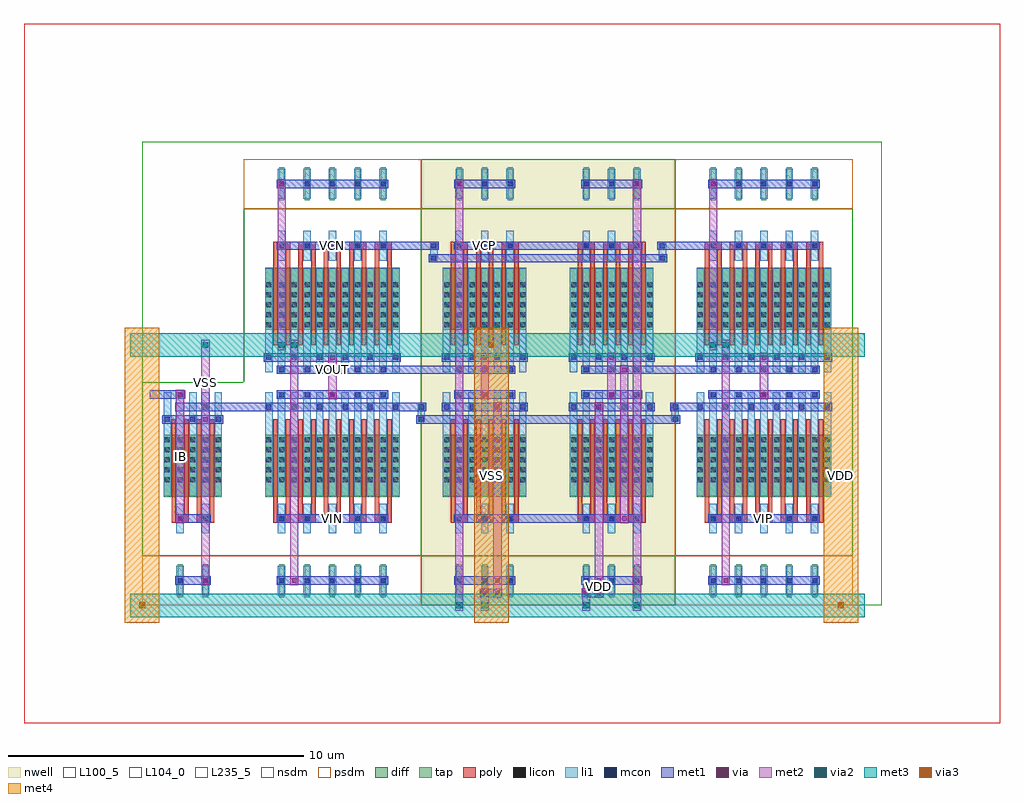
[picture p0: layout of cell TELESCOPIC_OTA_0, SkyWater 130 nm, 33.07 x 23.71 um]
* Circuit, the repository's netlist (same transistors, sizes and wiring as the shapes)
* NGSPICE file created from TELESCOPIC_OTA_0.ext - technology: sky130A

.subckt PMOS_4T_54671542_X3_Y1_1772448769 a_230_357# a_200_252# a_147_357# w_0_0#
X0 a_230_357# a_200_252# a_147_357# w_0_0# sky130_fd_pr__pfet_01v8 ad=0.294 pd=2.38 as=0.5565 ps=4.73 w=2.1 l=0.15 M=6
.ends

.subckt SCM_NMOS_4295876_X1_Y1_1772448771 a_200_252# a_402_357# a_147_357#
X0 a_200_252# a_200_252# a_147_357# a_147_357# sky130_fd_pr__nfet_01v8 ad=0.294 pd=2.38 as=0.5565 ps=4.73 w=2.1 l=0.15 M=2
X1 a_402_357# a_200_252# a_147_357# a_147_357# sky130_fd_pr__nfet_01v8 ad=0.294 pd=2.38 as=0.294 ps=2.38 w=2.1 l=0.15 M=2
.ends

.subckt NMOS_4T_2477428_X5_Y1_1772448768 a_230_357# a_200_252# a_147_357# a_241_1232#
X0 a_230_357# a_200_252# a_147_357# a_241_1232# sky130_fd_pr__nfet_01v8 ad=0.294 pd=2.38 as=0.294 ps=2.38 w=2.1 l=0.15 M=10
.ends

.subckt PMOS_S_62155954_X3_Y1_1772448770 a_230_357# a_200_252# w_0_0#
X0 a_230_357# a_200_252# w_0_0# w_0_0# sky130_fd_pr__pfet_01v8 ad=0.294 pd=2.38 as=0.5565 ps=4.73 w=2.1 l=0.15 M=6
.ends

.subckt TELESCOPIC_OTA_0 IB VCN VOUT VIP VIN VCP VSS VDD
XPMOS_4T_54671542_X3_Y1_1772448769_0 VOUT VCP m1_2290_1400# VDD PMOS_4T_54671542_X3_Y1_1772448769
XPMOS_4T_54671542_X3_Y1_1772448769_1 m1_3236_560# VCP m1_3150_1400# VDD PMOS_4T_54671542_X3_Y1_1772448769
XSCM_NMOS_4295876_X1_Y1_1772448771_0 IB m1_430_1316# VSS SCM_NMOS_4295876_X1_Y1_1772448771
XNMOS_4T_2477428_X5_Y1_1772448768_1 m1_4182_1400# VIP m1_430_1316# VSS NMOS_4T_2477428_X5_Y1_1772448768
XNMOS_4T_2477428_X5_Y1_1772448768_0 m1_1258_1400# VIN m1_430_1316# VSS NMOS_4T_2477428_X5_Y1_1772448768
XNMOS_4T_2477428_X5_Y1_1772448768_2 VOUT VCN m1_1258_1400# VSS NMOS_4T_2477428_X5_Y1_1772448768
XNMOS_4T_2477428_X5_Y1_1772448768_3 m1_3236_560# VCN m1_4182_1400# VSS NMOS_4T_2477428_X5_Y1_1772448768
XPMOS_S_62155954_X3_Y1_1772448770_0 m1_2290_1400# m1_3236_560# VDD PMOS_S_62155954_X3_Y1_1772448770
XPMOS_S_62155954_X3_Y1_1772448770_1 m1_3150_1400# m1_3236_560# VDD PMOS_S_62155954_X3_Y1_1772448770
.ends

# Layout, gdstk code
from math import pi, radians
import gdstk
lib = gdstk.Library(unit=1e-6, precision=1e-09)
def R(c, l, rs):  # rectangles x0, y0, x1, y1
    for r in rs: c.add(gdstk.rectangle(r[:2], r[2:], *l))
def A(c, l, x, y, w, h, nx, ny, dx, dy):  # array of equal rectangles
    R(c, l, [(x+i*dx, y+j*dy, x+i*dx+w, y+j*dy+h) for i in range(nx) for j in range(ny)])
def P(c, l, *ps):  # polygons
    for p in ps: c.add(gdstk.Polygon(p, *l))
nwell = (64, 20)
diff = (65, 20)
tap = (65, 44)
poly = (66, 20)
licon = (66, 44)
li1 = (67, 20)
mcon = (67, 44)
met1 = (68, 20)
via = (68, 44)
met2 = (69, 20)
via2 = (69, 44)
met3 = (70, 20)
via3 = (70, 44)
met4 = (71, 20)
nsdm = (93, 44)
psdm = (94, 20)
L100_5 = (100, 5)
L104_0 = (104, 0)
L235_5 = (235, 5)

scm_nmos_4295876_x1_y1_1 = lib.new_cell('SCM_NMOS_4295876_X1_Y1_1772448771')
R(scm_nmos_4295876_x1_y1_1, diff, [(0.735,1.785,2.705,3.885)])
R(scm_nmos_4295876_x1_y1_1, tap, [(1.205,6.16,1.375,7.28), (2.065,6.16,2.235,7.28)])
A(scm_nmos_4295876_x1_y1_1, poly, 1, 1.26, 0.15, 3.36, 4, 1, 0.43, 0)
R(scm_nmos_4295876_x1_y1_1, poly, [(1,4.485,1.58,4.755), (1.86,4.485,2.44,4.755)])
A(scm_nmos_4295876_x1_y1_1, licon, 0.775, 1.865, 0.17, 0.17, 3, 5, 0.43, 0.34)
A(scm_nmos_4295876_x1_y1_1, licon, 1.635, 1.865, 0.17, 0.17, 3, 5, 0.43, 0.34)
R(scm_nmos_4295876_x1_y1_1, licon, [(1.205,4.535,1.375,4.705), (2.065,4.535,2.235,4.705), (1.205,6.635,1.375,6.805), (2.065,6.635,2.235,6.805)])
A(scm_nmos_4295876_x1_y1_1, li1, 0.735, 0.335, 0.25, 3.53, 5, 1, 0.43, 0)
R(scm_nmos_4295876_x1_y1_1, li1, [(1.165,4.115,1.415,5.125), (2.025,4.115,2.275,5.125), (1.165,6.215,1.415,7.225), (2.025,6.215,2.275,7.225)])
A(scm_nmos_4295876_x1_y1_1, mcon, 0.775, 1.175, 0.17, 0.17, 3, 1, 0.86, 0)
R(scm_nmos_4295876_x1_y1_1, mcon, [(1.205,0.335,1.375,0.505), (2.065,0.755,2.235,0.925), (1.205,4.535,1.375,4.705), (2.065,4.535,2.235,4.705), (1.205,6.635,1.375,6.805), (2.065,6.635,2.235,6.805)])
R(scm_nmos_4295876_x1_y1_1, met1, [(0.26,0.28,1.46,0.56), (1.12,0.7,2.32,0.98), (0.69,1.12,2.75,1.4), (1.12,4.48,2.32,4.76), (1.12,6.58,2.32,6.86)])
R(scm_nmos_4295876_x1_y1_1, via, [(1.215,0.345,1.365,0.495), (2.075,1.185,2.225,1.335), (1.215,4.545,1.365,4.695), (2.075,6.645,2.225,6.795)])
R(scm_nmos_4295876_x1_y1_1, met2, [(1.15,0.26,1.43,4.78), (2.01,1.1,2.29,6.88)])
R(scm_nmos_4295876_x1_y1_1, nsdm, [(0,0,3.44,5.88)])
R(scm_nmos_4295876_x1_y1_1, psdm, [(0,5.88,3.44,7.56)])
R(scm_nmos_4295876_x1_y1_1, L100_5, [(0,0,3.44,7.56)])

pmos_s_62155954_x3_y1_17 = lib.new_cell('PMOS_S_62155954_X3_Y1_1772448770')
R(pmos_s_62155954_x3_y1_17, nwell, [(0,0,4.3,7.56)])
R(pmos_s_62155954_x3_y1_17, diff, [(0.735,1.785,3.565,3.885)])
A(pmos_s_62155954_x3_y1_17, tap, 1.205, 6.16, 0.17, 1.12, 3, 1, 0.86, 0)
A(pmos_s_62155954_x3_y1_17, poly, 1, 1.26, 0.15, 3.36, 6, 1, 0.43, 0)
A(pmos_s_62155954_x3_y1_17, poly, 1, 4.485, 0.58, 0.27, 3, 1, 0.86, 0)
A(pmos_s_62155954_x3_y1_17, licon, 0.775, 1.865, 0.17, 0.17, 3, 5, 0.43, 0.34)
A(pmos_s_62155954_x3_y1_17, licon, 1.635, 1.865, 0.17, 0.17, 3, 5, 0.43, 0.34)
A(pmos_s_62155954_x3_y1_17, licon, 2.495, 1.865, 0.17, 0.17, 3, 5, 0.43, 0.34)
A(pmos_s_62155954_x3_y1_17, licon, 1.205, 4.535, 0.17, 0.17, 3, 2, 0.86, 2.1)
A(pmos_s_62155954_x3_y1_17, li1, 0.735, 0.335, 0.25, 3.53, 7, 1, 0.43, 0)
A(pmos_s_62155954_x3_y1_17, li1, 1.165, 4.115, 0.25, 1.01, 3, 2, 0.86, 2.1)
A(pmos_s_62155954_x3_y1_17, mcon, 1.205, 0.335, 0.17, 0.17, 3, 2, 0.86, 4.2)
A(pmos_s_62155954_x3_y1_17, mcon, 0.775, 0.755, 0.17, 0.17, 4, 1, 0.86, 0)
A(pmos_s_62155954_x3_y1_17, mcon, 1.205, 6.635, 0.17, 0.17, 3, 1, 0.86, 0)
R(pmos_s_62155954_x3_y1_17, met1, [(1.12,0.28,3.18,0.56), (0.69,0.7,3.61,0.98), (1.12,4.48,3.18,4.76), (1.12,6.58,3.18,6.86)])
R(pmos_s_62155954_x3_y1_17, via, [(2.505,0.765,2.655,0.915), (2.505,6.645,2.655,6.795)])
R(pmos_s_62155954_x3_y1_17, met2, [(2.44,0.68,2.72,6.88)])
R(pmos_s_62155954_x3_y1_17, nsdm, [(0,5.88,4.3,7.56)])
R(pmos_s_62155954_x3_y1_17, psdm, [(0,0,4.3,5.88)])
R(pmos_s_62155954_x3_y1_17, L100_5, [(0,0,4.3,7.56)])

nmos_4t_2477428_x5_y1_17 = lib.new_cell('NMOS_4T_2477428_X5_Y1_1772448768')
R(nmos_4t_2477428_x5_y1_17, diff, [(0.735,1.785,5.285,3.885)])
A(nmos_4t_2477428_x5_y1_17, tap, 1.205, 6.16, 0.17, 1.12, 5, 1, 0.86, 0)
A(nmos_4t_2477428_x5_y1_17, poly, 1, 1.26, 0.15, 3.36, 10, 1, 0.43, 0)
A(nmos_4t_2477428_x5_y1_17, poly, 1, 4.485, 0.58, 0.27, 5, 1, 0.86, 0)
A(nmos_4t_2477428_x5_y1_17, licon, 0.775, 1.865, 0.17, 0.17, 3, 5, 0.43, 0.34)
A(nmos_4t_2477428_x5_y1_17, licon, 1.635, 1.865, 0.17, 0.17, 3, 5, 0.43, 0.34)
A(nmos_4t_2477428_x5_y1_17, licon, 2.495, 1.865, 0.17, 0.17, 3, 5, 0.43, 0.34)
A(nmos_4t_2477428_x5_y1_17, licon, 3.355, 1.865, 0.17, 0.17, 3, 5, 0.43, 0.34)
A(nmos_4t_2477428_x5_y1_17, licon, 4.215, 1.865, 0.17, 0.17, 3, 5, 0.43, 0.34)
A(nmos_4t_2477428_x5_y1_17, licon, 1.205, 4.535, 0.17, 0.17, 5, 2, 0.86, 2.1)
A(nmos_4t_2477428_x5_y1_17, li1, 0.735, 0.335, 0.25, 3.53, 11, 1, 0.43, 0)
A(nmos_4t_2477428_x5_y1_17, li1, 1.165, 4.115, 0.25, 1.01, 5, 2, 0.86, 2.1)
A(nmos_4t_2477428_x5_y1_17, mcon, 1.205, 0.335, 0.17, 0.17, 5, 2, 0.86, 4.2)
A(nmos_4t_2477428_x5_y1_17, mcon, 0.775, 0.755, 0.17, 0.17, 6, 1, 0.86, 0)
A(nmos_4t_2477428_x5_y1_17, mcon, 1.205, 6.635, 0.17, 0.17, 5, 1, 0.86, 0)
R(nmos_4t_2477428_x5_y1_17, met1, [(1.12,0.28,4.9,0.56), (0.69,0.7,5.33,0.98), (1.12,4.48,4.9,4.76), (1.12,6.58,4.9,6.86)])
R(nmos_4t_2477428_x5_y1_17, nsdm, [(0,0,6.02,5.88)])
R(nmos_4t_2477428_x5_y1_17, psdm, [(0,5.88,6.02,7.56)])
R(nmos_4t_2477428_x5_y1_17, L100_5, [(0,0,6.02,7.56)])

pmos_4t_54671542_x3_y1_1 = lib.new_cell('PMOS_4T_54671542_X3_Y1_1772448769')
R(pmos_4t_54671542_x3_y1_1, nwell, [(0,0,4.3,7.56)])
R(pmos_4t_54671542_x3_y1_1, diff, [(0.735,1.785,3.565,3.885)])
A(pmos_4t_54671542_x3_y1_1, tap, 1.205, 6.16, 0.17, 1.12, 3, 1, 0.86, 0)
A(pmos_4t_54671542_x3_y1_1, poly, 1, 1.26, 0.15, 3.36, 6, 1, 0.43, 0)
A(pmos_4t_54671542_x3_y1_1, poly, 1, 4.485, 0.58, 0.27, 3, 1, 0.86, 0)
A(pmos_4t_54671542_x3_y1_1, licon, 0.775, 1.865, 0.17, 0.17, 3, 5, 0.43, 0.34)
A(pmos_4t_54671542_x3_y1_1, licon, 1.635, 1.865, 0.17, 0.17, 3, 5, 0.43, 0.34)
A(pmos_4t_54671542_x3_y1_1, licon, 2.495, 1.865, 0.17, 0.17, 3, 5, 0.43, 0.34)
A(pmos_4t_54671542_x3_y1_1, licon, 1.205, 4.535, 0.17, 0.17, 3, 2, 0.86, 2.1)
A(pmos_4t_54671542_x3_y1_1, li1, 0.735, 0.335, 0.25, 3.53, 7, 1, 0.43, 0)
A(pmos_4t_54671542_x3_y1_1, li1, 1.165, 4.115, 0.25, 1.01, 3, 2, 0.86, 2.1)
A(pmos_4t_54671542_x3_y1_1, mcon, 1.205, 0.335, 0.17, 0.17, 3, 2, 0.86, 4.2)
A(pmos_4t_54671542_x3_y1_1, mcon, 0.775, 0.755, 0.17, 0.17, 4, 1, 0.86, 0)
A(pmos_4t_54671542_x3_y1_1, mcon, 1.205, 6.635, 0.17, 0.17, 3, 1, 0.86, 0)
R(pmos_4t_54671542_x3_y1_1, met1, [(1.12,0.28,3.18,0.56), (0.69,0.7,3.61,0.98), (1.12,4.48,3.18,4.76), (1.12,6.58,3.18,6.86)])
R(pmos_4t_54671542_x3_y1_1, nsdm, [(0,5.88,4.3,7.56)])
R(pmos_4t_54671542_x3_y1_1, psdm, [(0,0,4.3,5.88)])
R(pmos_4t_54671542_x3_y1_1, L100_5, [(0,0,4.3,7.56)])

telescopic_ota_0 = lib.new_cell('TELESCOPIC_OTA_0')
R(telescopic_ota_0, li1, [(9.335,6.215,9.585,6.385), (9.335,6.215,9.585,6.385), (17.935,6.215,18.185,6.385), (17.935,6.215,18.185,6.385), (9.335,6.3,9.585,6.72), (17.935,6.3,18.185,6.72), (9.335,6.635,9.585,6.805), (9.335,6.635,9.585,6.805), (17.935,6.635,18.185,6.805), (17.935,6.635,18.185,6.805), (9.765,11.675,10.015,11.845), (9.765,11.675,10.015,11.845), (17.505,11.675,17.755,11.845), (17.505,11.675,17.755,11.845), (9.765,11.76,10.015,12.18), (17.505,11.76,17.755,12.18), (9.765,12.095,10.015,12.265), (9.765,12.095,10.015,12.265), (17.505,12.095,17.755,12.265), (17.505,12.095,17.755,12.265)])
R(telescopic_ota_0, mcon, [(9.375,6.215,9.545,6.385), (9.375,6.215,9.545,6.385), (17.975,6.215,18.145,6.385), (17.975,6.215,18.145,6.385), (9.375,6.635,9.545,6.805), (9.375,6.635,9.545,6.805), (17.975,6.635,18.145,6.805), (17.975,6.635,18.145,6.805), (9.805,11.675,9.975,11.845), (9.805,11.675,9.975,11.845), (17.545,11.675,17.715,11.845), (17.545,11.675,17.715,11.845), (9.805,12.095,9.975,12.265), (9.805,12.095,9.975,12.265), (17.545,12.095,17.715,12.265), (17.545,12.095,17.715,12.265)])
R(telescopic_ota_0, met1, [(11.45,0.28,11.77,0.56), (11.45,0.28,11.77,0.56), (11.45,0.28,11.77,0.56), (11.45,0.28,11.77,0.56), (11.61,0.28,12.04,0.56), (11.88,0.28,12.2,0.56), (11.88,0.28,12.2,0.56), (11.88,0.28,12.2,0.56), (11.88,0.28,12.2,0.56), (14.89,0.28,15.21,0.56), (14.89,0.28,15.21,0.56), (14.89,0.28,15.21,0.56), (14.89,0.28,15.21,0.56), (14.89,0.28,15.21,0.56), (15.05,0.28,15.48,0.56), (15.32,0.28,15.64,0.56), (15.32,0.28,15.64,0.56), (15.32,0.28,15.64,0.56), (15.32,0.28,15.64,0.56), (15.32,0.28,15.64,0.56), (5,0.7,5.32,0.98), (5,0.7,5.32,0.98), (19.62,0.7,19.94,0.98), (19.62,0.7,19.94,0.98), (19.62,0.7,19.94,0.98), (12.47,2.8,15.05,3.08), (16.18,2.8,16.5,3.08), (16.18,2.8,16.5,3.08), (16.18,2.8,16.5,3.08), (16.18,2.8,16.5,3.08), (9.29,6.16,9.63,6.44), (9.29,6.16,9.63,6.44), (9.46,6.16,18.06,6.44), (17.89,6.16,18.23,6.44), (17.89,6.16,18.23,6.44), (2.15,6.58,4.3,6.86), (8.6,6.58,9.46,6.86), (9.29,6.58,9.63,6.86), (9.29,6.58,9.63,6.86), (17.89,6.58,18.23,6.86), (17.89,6.58,18.23,6.86), (18.06,6.58,18.92,6.86), (6.29,7,6.61,7.28), (6.29,7,6.61,7.28), (11.45,7,11.77,7.28), (11.45,7,11.77,7.28), (15.75,7,16.07,7.28), (15.75,7,16.07,7.28), (20.91,7,21.23,7.28), (20.91,7,21.23,7.28), (8.17,7.84,10.75,8.12), (16.18,7.84,16.5,8.12), (16.18,7.84,16.5,8.12), (16.18,7.84,16.5,8.12), (16.18,7.84,16.5,8.12), (16.77,7.84,19.35,8.12), (6.29,8.26,6.61,8.54), (6.29,8.26,6.61,8.54), (11.45,8.26,11.77,8.54), (11.45,8.26,11.77,8.54), (15.75,8.26,16.07,8.54), (15.75,8.26,16.07,8.54), (20.91,8.26,21.23,8.54), (20.91,8.26,21.23,8.54), (9.72,11.62,10.06,11.9), (9.72,11.62,10.06,11.9), (9.89,11.62,17.63,11.9), (17.46,11.62,17.8,11.9), (17.46,11.62,17.8,11.9), (8.17,12.04,9.89,12.32), (9.72,12.04,10.06,12.32), (9.72,12.04,10.06,12.32), (12.47,12.04,15.05,12.32), (17.46,12.04,17.8,12.32), (17.46,12.04,17.8,12.32), (17.63,12.04,19.35,12.32), (4.57,14.14,4.89,14.42), (4.57,14.14,4.89,14.42), (4.57,14.14,4.89,14.42), (4.57,14.14,4.89,14.42), (10.59,14.14,10.91,14.42), (10.59,14.14,10.91,14.42), (16.61,14.14,16.93,14.42), (16.61,14.14,16.93,14.42), (16.61,14.14,16.93,14.42), (19.19,14.14,19.51,14.42), (19.19,14.14,19.51,14.42), (19.19,14.14,19.51,14.42), (19.19,14.14,19.51,14.42), (19.19,14.14,19.51,14.42)])
P(telescopic_ota_0, met1, [(0,0),(0,0),(0,0),(0,0)],
  [(0,0),(0,0),(0,0),(0,0)],
  [(0,0),(0,0),(0,0),(0,0)],
  [(0,0),(0,0),(0,0),(0,0)],
  [(0,0),(0,0),(0,0),(0,0)],
  [(0,0),(0,0),(0,0),(0,0)],
  [(0,0),(0,0),(0,0),(0,0)],
  [(0,0),(0,0),(0,0),(0,0)],
  [(0,0),(0,0),(0,0),(0,0)],
  [(0,0),(0,0),(0,0),(0,0)],
  [(0,0),(0,0),(0,0),(0,0)],
  [(0,0),(0,0),(0,0),(0,0)],
  [(0,0),(0,0),(0,0),(0,0)],
  [(0,0),(0,0),(0,0),(0,0)],
  [(0,0),(0,0),(0,0),(0,0)],
  [(0,0),(0,0),(0,0),(0,0)],
  [(0,0),(0,0),(0,0),(0,0)],
  [(0,0),(0,0),(0,0),(0,0)],
  [(0,0),(0,0),(0,0),(0,0)],
  [(0,0),(0,0),(0,0),(0,0)],
  [(0,0),(0,0),(0,0),(0,0)],
  [(0,0),(0,0),(0,0),(0,0)],
  [(0,0),(0,0),(0,0),(0,0)],
  [(0,0),(0,0),(0,0),(0,0)],
  [(0,0),(0,0),(0,0),(0,0)],
  [(0,0),(0,0),(0,0),(0,0)],
  [(0,0),(0,0),(0,0),(0,0)],
  [(0,0),(0,0),(0,0),(0,0)],
  [(0,0),(0,0),(0,0),(0,0)],
  [(0,0),(0,0),(0,0),(0,0)],
  [(0,0),(0,0),(0,0),(0,0)],
  [(0,0),(0,0),(0,0),(0,0)],
  [(0,0),(0,0),(0,0),(0,0)],
  [(0,0),(0,0),(0,0),(0,0)])
R(telescopic_ota_0, via, [(11.535,0.345,11.685,0.495), (11.535,0.345,11.685,0.495), (11.535,0.345,11.685,0.495), (11.535,0.345,11.685,0.495), (11.965,0.345,12.115,0.495), (11.965,0.345,12.115,0.495), (11.965,0.345,12.115,0.495), (11.965,0.345,12.115,0.495), (14.975,0.345,15.125,0.495), (14.975,0.345,15.125,0.495), (14.975,0.345,15.125,0.495), (14.975,0.345,15.125,0.495), (14.975,0.345,15.125,0.495), (15.405,0.345,15.555,0.495), (15.405,0.345,15.555,0.495), (15.405,0.345,15.555,0.495), (15.405,0.345,15.555,0.495), (15.405,0.345,15.555,0.495), (5.085,0.765,5.235,0.915), (5.085,0.765,5.235,0.915), (19.705,0.765,19.855,0.915), (19.705,0.765,19.855,0.915), (19.705,0.765,19.855,0.915), (16.265,2.865,16.415,3.015), (16.265,2.865,16.415,3.015), (16.265,2.865,16.415,3.015), (16.265,2.865,16.415,3.015), (6.375,7.065,6.525,7.215), (6.375,7.065,6.525,7.215), (11.535,7.065,11.685,7.215), (11.535,7.065,11.685,7.215), (15.835,7.065,15.985,7.215), (15.835,7.065,15.985,7.215), (20.995,7.065,21.145,7.215), (20.995,7.065,21.145,7.215), (16.265,7.905,16.415,8.055), (16.265,7.905,16.415,8.055), (16.265,7.905,16.415,8.055), (16.265,7.905,16.415,8.055), (6.375,8.325,6.525,8.475), (6.375,8.325,6.525,8.475), (11.535,8.325,11.685,8.475), (11.535,8.325,11.685,8.475), (15.835,8.325,15.985,8.475), (15.835,8.325,15.985,8.475), (20.995,8.325,21.145,8.475), (20.995,8.325,21.145,8.475), (4.655,14.205,4.805,14.355), (4.655,14.205,4.805,14.355), (4.655,14.205,4.805,14.355), (4.655,14.205,4.805,14.355), (10.675,14.205,10.825,14.355), (10.675,14.205,10.825,14.355), (16.695,14.205,16.845,14.355), (16.695,14.205,16.845,14.355), (16.695,14.205,16.845,14.355), (19.275,14.205,19.425,14.355), (19.275,14.205,19.425,14.355), (19.275,14.205,19.425,14.355), (19.275,14.205,19.425,14.355), (19.275,14.205,19.425,14.355)])
R(telescopic_ota_0, met2, [(10.61,-0.185,10.89,0.185), (10.61,-0.185,10.89,0.185), (11.47,-0.185,11.75,0.185), (11.47,-0.185,11.75,0.185), (11.47,-0.185,11.75,0.185), (11.47,-0.185,11.75,0.185), (14.91,-0.185,15.19,0.185), (14.91,-0.185,15.19,0.185), (14.91,-0.185,15.19,0.185), (14.91,-0.185,15.19,0.185), (14.91,-0.185,15.19,0.185), (16.63,-0.185,16.91,0.185), (16.63,-0.185,16.91,0.185), (16.63,-0.185,16.91,0.185), (10.61,0,10.89,14.28), (11.47,0,11.75,0.42), (14.91,0,15.19,0.42), (16.63,0,16.91,14.28), (11.47,0.26,11.75,0.58), (11.47,0.26,11.75,0.58), (11.47,0.26,11.75,0.58), (11.47,0.26,11.75,0.58), (11.9,0.26,12.18,0.58), (11.9,0.26,12.18,0.58), (11.9,0.26,12.18,0.58), (11.9,0.26,12.18,0.58), (14.91,0.26,15.19,0.58), (14.91,0.26,15.19,0.58), (14.91,0.26,15.19,0.58), (14.91,0.26,15.19,0.58), (14.91,0.26,15.19,0.58), (15.34,0.26,15.62,0.58), (15.34,0.26,15.62,0.58), (15.34,0.26,15.62,0.58), (15.34,0.26,15.62,0.58), (15.34,0.26,15.62,0.58), (11.9,0.42,12.18,0.84), (15.34,0.42,15.62,0.84), (5.02,0.68,5.3,1), (5.02,0.68,5.3,1), (19.64,0.68,19.92,1), (19.64,0.68,19.92,1), (19.64,0.68,19.92,1), (5.02,0.84,5.3,8.82), (19.64,0.84,19.92,8.82), (16.2,2.78,16.48,3.1), (16.2,2.78,16.48,3.1), (16.2,2.78,16.48,3.1), (16.2,2.78,16.48,3.1), (16.2,2.94,16.48,7.98), (2.01,6.3,2.29,8.82), (6.31,6.98,6.59,7.3), (6.31,6.98,6.59,7.3), (11.47,6.98,11.75,7.3), (11.47,6.98,11.75,7.3), (15.77,6.98,16.05,7.3), (15.77,6.98,16.05,7.3), (20.93,6.98,21.21,7.3), (20.93,6.98,21.21,7.3), (6.31,7.14,6.59,8.4), (11.47,7.14,11.75,8.4), (15.77,7.14,16.05,8.4), (20.93,7.14,21.21,8.4), (16.2,7.82,16.48,8.14), (16.2,7.82,16.48,8.14), (16.2,7.82,16.48,8.14), (16.2,7.82,16.48,8.14), (6.31,8.24,6.59,8.56), (6.31,8.24,6.59,8.56), (11.47,8.24,11.75,8.56), (11.47,8.24,11.75,8.56), (15.77,8.24,16.05,8.56), (15.77,8.24,16.05,8.56), (20.93,8.24,21.21,8.56), (20.93,8.24,21.21,8.56), (2.01,8.635,2.29,9.005), (2.01,8.635,2.29,9.005), (2.01,8.635,2.29,9.005), (2.01,8.635,2.29,9.005), (2.01,8.635,2.29,9.005), (2.01,8.635,2.29,9.005), (4.59,8.635,4.87,9.005), (4.59,8.635,4.87,9.005), (4.59,8.635,4.87,9.005), (4.59,8.635,4.87,9.005), (5.02,8.635,5.3,9.005), (5.02,8.635,5.3,9.005), (19.21,8.635,19.49,9.005), (19.21,8.635,19.49,9.005), (19.21,8.635,19.49,9.005), (19.21,8.635,19.49,9.005), (19.21,8.635,19.49,9.005), (19.64,8.635,19.92,9.005), (19.64,8.635,19.92,9.005), (19.64,8.635,19.92,9.005), (4.59,8.82,4.87,14.28), (19.21,8.82,19.49,14.28), (4.59,14.12,4.87,14.44), (4.59,14.12,4.87,14.44), (4.59,14.12,4.87,14.44), (4.59,14.12,4.87,14.44), (10.61,14.12,10.89,14.44), (10.61,14.12,10.89,14.44), (16.63,14.12,16.91,14.44), (16.63,14.12,16.91,14.44), (16.63,14.12,16.91,14.44), (19.21,14.12,19.49,14.44), (19.21,14.12,19.49,14.44), (19.21,14.12,19.49,14.44), (19.21,14.12,19.49,14.44), (19.21,14.12,19.49,14.44)])
P(telescopic_ota_0, met2, [(0,0),(0,0),(0,0),(0,0)],
  [(0,0),(0,0),(0,0),(0,0)],
  [(0,0),(0,0),(0,0),(0,0)],
  [(0,0),(0,0),(0,0),(0,0)],
  [(0,0),(0,0),(0,0),(0,0)])
R(telescopic_ota_0, via2, [(10.65,-0.1,10.85,0.1), (10.65,-0.1,10.85,0.1), (11.51,-0.1,11.71,0.1), (11.51,-0.1,11.71,0.1), (11.51,-0.1,11.71,0.1), (11.51,-0.1,11.71,0.1), (14.95,-0.1,15.15,0.1), (14.95,-0.1,15.15,0.1), (14.95,-0.1,15.15,0.1), (14.95,-0.1,15.15,0.1), (14.95,-0.1,15.15,0.1), (16.67,-0.1,16.87,0.1), (16.67,-0.1,16.87,0.1), (16.67,-0.1,16.87,0.1), (2.05,8.72,2.25,8.92), (2.05,8.72,2.25,8.92), (2.05,8.72,2.25,8.92), (2.05,8.72,2.25,8.92), (2.05,8.72,2.25,8.92), (2.05,8.72,2.25,8.92), (4.63,8.72,4.83,8.92), (4.63,8.72,4.83,8.92), (4.63,8.72,4.83,8.92), (4.63,8.72,4.83,8.92), (5.06,8.72,5.26,8.92), (5.06,8.72,5.26,8.92), (19.25,8.72,19.45,8.92), (19.25,8.72,19.45,8.92), (19.25,8.72,19.45,8.92), (19.25,8.72,19.45,8.92), (19.25,8.72,19.45,8.92), (19.68,8.72,19.88,8.92), (19.68,8.72,19.88,8.92), (19.68,8.72,19.88,8.92)])
A(telescopic_ota_0, met3, -0.4, -0.4, 4.24, 0.8, 3, 2, 3.44, 8.82)
R(telescopic_ota_0, met3, [(-0.165,-0.4,0.165,0.4), (9.92,-0.4,12.24,0.4), (10.585,-0.4,10.915,0.4), (10.585,-0.4,10.915,0.4), (11.44,-0.4,14.16,0.4), (11.445,-0.4,11.775,0.4), (11.445,-0.4,11.775,0.4), (11.445,-0.4,11.775,0.4), (11.445,-0.4,11.775,0.4), (13.36,-0.4,17.6,0.4), (14.885,-0.4,15.215,0.4), (14.885,-0.4,15.215,0.4), (14.885,-0.4,15.215,0.4), (14.885,-0.4,15.215,0.4), (14.885,-0.4,15.215,0.4), (16.605,-0.4,16.935,0.4), (16.605,-0.4,16.935,0.4), (16.605,-0.4,16.935,0.4), (16.8,-0.4,21.04,0.4), (20.24,-0.4,24.08,0.4), (23.28,-0.4,24.48,0.4), (23.515,-0.4,23.845,0.4), (1.985,8.42,2.315,9.22), (1.985,8.42,2.315,9.22), (1.985,8.42,2.315,9.22), (1.985,8.42,2.315,9.22), (1.985,8.42,2.315,9.22), (1.985,8.42,2.315,9.22), (4.565,8.42,4.895,9.22), (4.565,8.42,4.895,9.22), (4.565,8.42,4.895,9.22), (4.565,8.42,4.895,9.22), (4.995,8.42,5.325,9.22), (4.995,8.42,5.325,9.22), (9.92,8.42,12.24,9.22), (11.44,8.42,14.16,9.22), (11.675,8.42,12.005,9.22), (13.36,8.42,17.6,9.22), (16.8,8.42,21.04,9.22), (19.185,8.42,19.515,9.22), (19.185,8.42,19.515,9.22), (19.185,8.42,19.515,9.22), (19.185,8.42,19.515,9.22), (19.185,8.42,19.515,9.22), (19.615,8.42,19.945,9.22), (19.615,8.42,19.945,9.22), (19.615,8.42,19.945,9.22), (20.24,8.42,24.08,9.22), (23.28,8.42,24.48,9.22)])
R(telescopic_ota_0, via3, [(-0.1,-0.1,0.1,0.1), (23.58,-0.1,23.78,0.1), (11.74,8.72,11.94,8.92)])
A(telescopic_ota_0, met4, -0.59, -0.59, 1.18, 10, 3, 1, 11.84, 0)
R(telescopic_ota_0, met4, [(-0.59,-0.165,0.59,0.165), (23.09,-0.165,24.27,0.165), (11.25,8.655,12.43,8.985)])
R(telescopic_ota_0, L104_0, [(-4,-4,29.07,19.71)])
R(telescopic_ota_0, L235_5, [(0,0,25.07,15.71)])
telescopic_ota_0.add(gdstk.Reference(scm_nmos_4295876_x1_y1_1, (0,7.56), x_reflection=True))
telescopic_ota_0.add(gdstk.Reference(pmos_s_62155954_x3_y1_17, (18.06,7.56), rotation=pi))
telescopic_ota_0.add(gdstk.Reference(pmos_s_62155954_x3_y1_17, (9.46,7.56), x_reflection=True))
telescopic_ota_0.add(gdstk.Reference(nmos_4t_2477428_x5_y1_17, (24.08,7.56), rotation=pi, x_reflection=True))
telescopic_ota_0.add(gdstk.Reference(nmos_4t_2477428_x5_y1_17, (3.44,7.56)))
telescopic_ota_0.add(gdstk.Reference(nmos_4t_2477428_x5_y1_17, (18.06,7.56), x_reflection=True))
telescopic_ota_0.add(gdstk.Reference(nmos_4t_2477428_x5_y1_17, (9.46,7.56), rotation=pi))
telescopic_ota_0.add(gdstk.Reference(pmos_4t_54671542_x3_y1_1, (13.76,7.56)))
telescopic_ota_0.add(gdstk.Reference(pmos_4t_54671542_x3_y1_1, (13.76,7.56), rotation=pi, x_reflection=True))
telescopic_ota_0.add(gdstk.Label('IB', (1.29,5.04), layer=69, texttype=5))
telescopic_ota_0.add(gdstk.Label('VCN', (6.45,12.18), layer=68, texttype=5))
telescopic_ota_0.add(gdstk.Label('VOUT', (6.45,7.98), layer=68, texttype=5))
telescopic_ota_0.add(gdstk.Label('VIP', (21.07,2.94), layer=68, texttype=5))
telescopic_ota_0.add(gdstk.Label('VIN', (6.45,2.94), layer=68, texttype=5))
telescopic_ota_0.add(gdstk.Label('VCP', (11.61,12.18), layer=68, texttype=5))
telescopic_ota_0.add(gdstk.Label('VSS', (2.15,7.56), layer=69, texttype=5))
telescopic_ota_0.add(gdstk.Label('VSS', (11.84,4.41), layer=71, texttype=5))
telescopic_ota_0.add(gdstk.Label('VSS', (11.84,4.41), layer=71, texttype=5))
telescopic_ota_0.add(gdstk.Label('VSS', (11.84,4.41), layer=71, texttype=5))
telescopic_ota_0.add(gdstk.Label('VSS', (11.84,4.41), layer=71, texttype=5))
telescopic_ota_0.add(gdstk.Label('VSS', (11.84,4.41), layer=71, texttype=5))
telescopic_ota_0.add(gdstk.Label('VSS', (11.84,4.41), layer=71, texttype=5))
telescopic_ota_0.add(gdstk.Label('VSS', (11.84,4.41), layer=71, texttype=5))
telescopic_ota_0.add(gdstk.Label('VSS', (11.84,4.41), layer=71, texttype=5))
telescopic_ota_0.add(gdstk.Label('VSS', (11.84,4.41), layer=71, texttype=5))
telescopic_ota_0.add(gdstk.Label('VSS', (11.84,4.41), layer=71, texttype=5))
telescopic_ota_0.add(gdstk.Label('VSS', (11.84,4.41), layer=71, texttype=5))
telescopic_ota_0.add(gdstk.Label('VSS', (11.84,4.41), layer=71, texttype=5))
telescopic_ota_0.add(gdstk.Label('VSS', (11.84,4.41), layer=71, texttype=5))
telescopic_ota_0.add(gdstk.Label('VSS', (11.84,4.41), layer=71, texttype=5))
telescopic_ota_0.add(gdstk.Label('VDD', (15.48,0.63), layer=69, texttype=5))
telescopic_ota_0.add(gdstk.Label('VDD', (23.68,4.41), layer=71, texttype=5))
telescopic_ota_0.add(gdstk.Label('VDD', (23.68,4.41), layer=71, texttype=5))
telescopic_ota_0.add(gdstk.Label('VDD', (23.68,4.41), layer=71, texttype=5))
telescopic_ota_0.add(gdstk.Label('VDD', (23.68,4.41), layer=71, texttype=5))
telescopic_ota_0.add(gdstk.Label('VDD', (23.68,4.41), layer=71, texttype=5))
telescopic_ota_0.add(gdstk.Label('VDD', (23.68,4.41), layer=71, texttype=5))
telescopic_ota_0.add(gdstk.Label('VDD', (23.68,4.41), layer=71, texttype=5))
telescopic_ota_0.add(gdstk.Label('VDD', (23.68,4.41), layer=71, texttype=5))
telescopic_ota_0.add(gdstk.Label('VDD', (23.68,4.41), layer=71, texttype=5))
telescopic_ota_0.add(gdstk.Label('VDD', (23.68,4.41), layer=71, texttype=5))
telescopic_ota_0.add(gdstk.Label('VDD', (23.68,4.41), layer=71, texttype=5))
telescopic_ota_0.add(gdstk.Label('VDD', (23.68,4.41), layer=71, texttype=5))
telescopic_ota_0.add(gdstk.Label('VDD', (23.68,4.41), layer=71, texttype=5))
telescopic_ota_0.add(gdstk.Label('VDD', (23.68,4.41), layer=71, texttype=5))

lib.write_gds('TELESCOPIC_OTA_0.gds')
